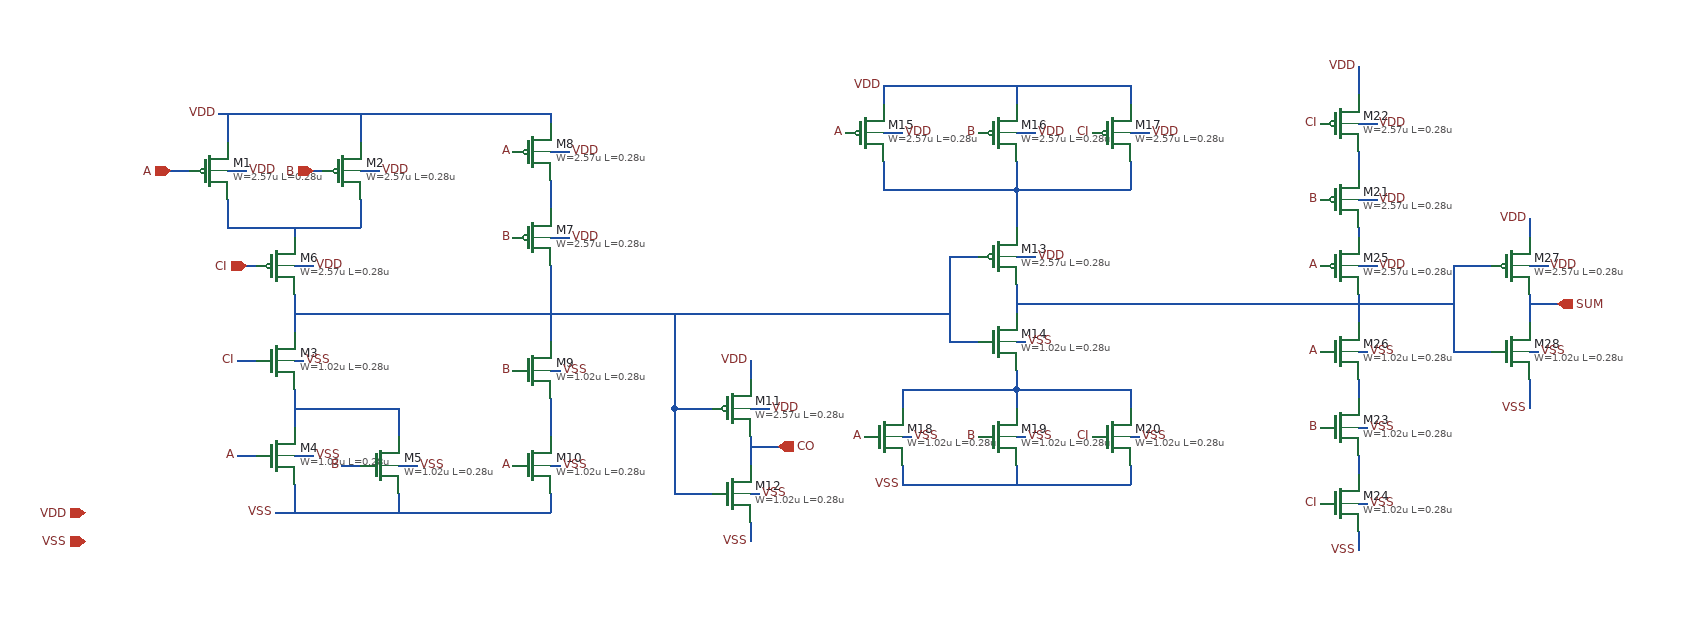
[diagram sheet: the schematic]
v {xschem version=3.4.6 file_version=1.2}
G {}
K {}
V {}
S {}
E {}
N 120 -480 120 -450 { lab=VDD}
N 260 -480 260 -450 { lab=VDD}
N 120 -390 120 -360 { lab=#net1}
N 120 -360 260 -360 { lab=#net1}
N 260 -390 260 -360 { lab=#net1}
N 190 -190 190 -150 { lab=#net2}
N 190 -90 190 -60 { lab=VSS}
N 60 -420 80 -420 { lab=A}
N 210 -420 220 -420 { lab=B}
N 190 -270 250 -270 { lab=#net3}
N 120 -420 140 -420 { lab=VDD}
N 260 -420 280 -420 { lab=VDD}
N 190 -220 200 -220 { lab=VSS}
N 190 -120 210 -120 { lab=VSS}
N 130 -220 150 -220 { lab=CI}
N 130 -120 150 -120 { lab=A}
N 140 -320 150 -320 { lab=CI}
N 190 -320 210 -320 { lab=VDD}
N 190 -360 190 -350 { lab=#net1}
N 190 -290 190 -250 { lab=#net3}
N 240 -110 260 -110 { lab=B}
N 300 -110 320 -110 { lab=VSS}
N 300 -80 300 -70 { lab=VSS}
N 190 -170 300 -170 { lab=#net2}
N 300 -170 300 -140 { lab=#net2}
N 300 -70 300 -60 { lab=VSS}
N 460 -410 460 -380 { lab=#net4}
N 460 -180 460 -140 { lab=#net5}
N 460 -320 460 -240 { lab=#net3}
N 460 -80 460 -60 { lab=VSS}
N 250 -270 460 -270 { lab=#net3}
N 670 -140 670 -110 { lab=CO}
N 590 -170 630 -170 { lab=#net3}
N 590 -170 590 -80 { lab=#net3}
N 590 -80 630 -80 { lab=#net3}
N 670 -220 670 -200 { lab=VDD}
N 460 -270 800 -270 { lab=#net3}
N 590 -270 590 -170 { lab=#net3}
N 950 -300 950 -270 { lab=#net6}
N 880 -330 920 -330 { lab=#net3}
N 880 -330 880 -240 { lab=#net3}
N 880 -240 920 -240 { lab=#net3}
N 810 -430 810 -400 { lab=#net7}
N 810 -400 950 -400 { lab=#net7}
N 950 -430 950 -400 { lab=#net7}
N 950 -400 1070 -400 { lab=#net7}
N 1070 -430 1070 -400 { lab=#net7}
N 950 -400 950 -360 { lab=#net7}
N 830 -190 830 -170 { lab=#net8}
N 900 -190 950 -190 { lab=#net8}
N 950 -200 950 -190 { lab=#net8}
N 950 -190 950 -170 { lab=#net8}
N 1070 -190 1070 -170 { lab=#net8}
N 460 -440 480 -440 { lab=VDD}
N 460 -350 480 -350 { lab=VDD}
N 810 -460 830 -460 { lab=VDD}
N 950 -460 970 -460 { lab=VDD}
N 1070 -460 1090 -460 { lab=VDD}
N 950 -330 970 -330 { lab=VDD}
N 460 -210 470 -210 { lab=VSS}
N 460 -110 470 -110 { lab=VSS}
N 670 -80 680 -80 { lab=VSS}
N 830 -140 840 -140 { lab=VSS}
N 950 -140 960 -140 { lab=VSS}
N 1070 -140 1080 -140 { lab=VSS}
N 950 -240 960 -240 { lab=VSS}
N 670 -170 690 -170 { lab=VDD}
N 950 -210 950 -200 { lab=#net8}
N 830 -190 900 -190 { lab=#net8}
N 950 -190 1070 -190 { lab=#net8}
N 1310 -40 1310 -20 { lab=VSS}
N 1310 -470 1330 -470 { lab=VDD}
N 1310 -390 1330 -390 { lab=VDD}
N 1310 -150 1320 -150 { lab=VSS}
N 1310 -70 1320 -70 { lab=VSS}
N 1310 -320 1330 -320 { lab=VDD}
N 1310 -360 1310 -350 { lab=#net9}
N 1310 -230 1320 -230 { lab=VSS}
N 1310 -200 1310 -180 { lab=#net10}
N 1310 -120 1310 -100 { lab=#net11}
N 1310 -440 1310 -420 { lab=#net12}
N 1310 -290 1310 -260 { lab=#net6}
N 800 -270 880 -270 { lab=#net3}
N 950 -280 1310 -280 { lab=#net6}
N 1490 -190 1490 -170 { lab=#net13}
N 1490 -200 1490 -190 { lab=#net13}
N 1490 -290 1490 -260 { lab=SUM}
N 1410 -320 1450 -320 { lab=#net6}
N 1410 -320 1410 -230 { lab=#net6}
N 1410 -230 1450 -230 { lab=#net6}
N 1490 -370 1490 -350 { lab=VDD}
N 1490 -230 1500 -230 { lab=VSS}
N 1490 -320 1510 -320 { lab=VDD}
N 1310 -280 1410 -280 { lab=#net6}
N 1490 -280 1520 -280 { lab=SUM}
N 670 -130 700 -130 {lab=CO}
N 460 -480 460 -470 {lab=VDD}
N 110 -480 460 -480 {lab=VDD}
N 170 -60 460 -60 {lab=VSS}
N 830 -110 830 -90 {lab=VSS}
N 830 -90 1070 -90 {lab=VSS}
N 1070 -110 1070 -90 {lab=VSS}
N 950 -110 950 -90 {lab=VSS}
N 1070 -510 1070 -490 {lab=VDD}
N 810 -510 1070 -510 {lab=VDD}
N 810 -510 810 -490 {lab=VDD}
N 950 -510 950 -490 {lab=VDD}
N 1310 -530 1310 -500 {lab=VDD}
N 670 -50 670 -30 {lab=VSS}
C {symbols/pfet_03v3.sym} 100 -420 0 0 {name=M1 L=0.28u W=2.57u m=1 nf=2 ad="'int((nf+1)/2) * W/nf * 0.18u'" pd="'2*int((nf+1)/2) * (W/nf + 0.18u)'" as="'int((nf+2)/2) * W/nf * 0.18u'" ps="'2*int((nf+2)/2) * (W/nf + 0.18u)'" nrd="'0.18u / W'" nrs="'0.18u / W'" sa=0 sb=0 sd=0 model=pfet_03v3 spiceprefix=X}
C {symbols/pfet_03v3.sym} 240 -420 0 0 {name=M2 L=0.28u W=2.57u m=1 nf=2 ad="'int((nf+1)/2) * W/nf * 0.18u'" pd="'2*int((nf+1)/2) * (W/nf + 0.18u)'" as="'int((nf+2)/2) * W/nf * 0.18u'" ps="'2*int((nf+2)/2) * (W/nf + 0.18u)'" nrd="'0.18u / W'" nrs="'0.18u / W'" sa=0 sb=0 sd=0 model=pfet_03v3 spiceprefix=X}
C {symbols/nfet_03v3.sym} 170 -220 0 0 {name=M3 L=0.28u W=1.02u m=1 nf=1 ad="'int((nf+1)/2) * W/nf * 0.18u'" pd="'2*int((nf+1)/2) * (W/nf + 0.18u)'" as="'int((nf+2)/2) * W/nf * 0.18u'" ps="'2*int((nf+2)/2) * (W/nf + 0.18u)'" nrd="'0.18u / W'" nrs="'0.18u / W'" sa=0 sb=0 sd=0 model=nfet_03v3 spiceprefix=X}
C {symbols/nfet_03v3.sym} 170 -120 0 0 {name=M4 L=0.28u W=1.02u m=1 nf=1 ad="'int((nf+1)/2) * W/nf * 0.18u'" pd="'2*int((nf+1)/2) * (W/nf + 0.18u)'" as="'int((nf+2)/2) * W/nf * 0.18u'" ps="'2*int((nf+2)/2) * (W/nf + 0.18u)'" nrd="'0.18u / W'" nrs="'0.18u / W'" sa=0 sb=0 sd=0 model=nfet_03v3 spiceprefix=X}
C {lab_wire.sym} 140 -420 2 0 {name=l4 sig_type=std_logic lab=VDD}
C {lab_wire.sym} 280 -420 2 0 {name=l5 sig_type=std_logic lab=VDD}
C {lab_wire.sym} 200 -220 2 0 {name=l6 sig_type=std_logic lab=VSS}
C {lab_wire.sym} 210 -120 2 0 {name=l7 sig_type=std_logic lab=VSS}
C {lab_wire.sym} 130 -220 0 0 {name=l8 sig_type=std_logic lab=CI
}
C {lab_wire.sym} 130 -120 0 0 {name=l9 sig_type=std_logic lab=A}
C {symbols/nfet_03v3.sym} 280 -110 0 0 {name=M5 L=0.28u W=1.02u m=1 nf=1 ad="'int((nf+1)/2) * W/nf * 0.18u'" pd="'2*int((nf+1)/2) * (W/nf + 0.18u)'" as="'int((nf+2)/2) * W/nf * 0.18u'" ps="'2*int((nf+2)/2) * (W/nf + 0.18u)'" nrd="'0.18u / W'" nrs="'0.18u / W'" sa=0 sb=0 sd=0 model=nfet_03v3 spiceprefix=X}
C {symbols/pfet_03v3.sym} 170 -320 0 0 {name=M6 L=0.28u W=2.57u m=1 nf=2 ad="'int((nf+1)/2) * W/nf * 0.18u'" pd="'2*int((nf+1)/2) * (W/nf + 0.18u)'" as="'int((nf+2)/2) * W/nf * 0.18u'" ps="'2*int((nf+2)/2) * (W/nf + 0.18u)'" nrd="'0.18u / W'" nrs="'0.18u / W'" sa=0 sb=0 sd=0 model=pfet_03v3 spiceprefix=X}
C {lab_wire.sym} 210 -320 2 0 {name=l10 sig_type=std_logic lab=VDD}
C {lab_wire.sym} 240 -110 0 0 {name=l11 sig_type=std_logic lab=B
}
C {lab_wire.sym} 320 -110 2 0 {name=l12 sig_type=std_logic lab=VSS}
C {symbols/pfet_03v3.sym} 440 -350 0 0 {name=M7 L=0.28u W=2.57u m=1 nf=2 ad="'int((nf+1)/2) * W/nf * 0.18u'" pd="'2*int((nf+1)/2) * (W/nf + 0.18u)'" as="'int((nf+2)/2) * W/nf * 0.18u'" ps="'2*int((nf+2)/2) * (W/nf + 0.18u)'" nrd="'0.18u / W'" nrs="'0.18u / W'" sa=0 sb=0 sd=0 model=pfet_03v3 spiceprefix=X}
C {symbols/pfet_03v3.sym} 440 -440 0 0 {name=M8 L=0.28u W=2.57u m=1 nf=2 ad="'int((nf+1)/2) * W/nf * 0.18u'" pd="'2*int((nf+1)/2) * (W/nf + 0.18u)'" as="'int((nf+2)/2) * W/nf * 0.18u'" ps="'2*int((nf+2)/2) * (W/nf + 0.18u)'" nrd="'0.18u / W'" nrs="'0.18u / W'" sa=0 sb=0 sd=0 model=pfet_03v3 spiceprefix=X}
C {symbols/nfet_03v3.sym} 440 -210 0 0 {name=M9 L=0.28u W=1.02u m=1 nf=1 ad="'int((nf+1)/2) * W/nf * 0.18u'" pd="'2*int((nf+1)/2) * (W/nf + 0.18u)'" as="'int((nf+2)/2) * W/nf * 0.18u'" ps="'2*int((nf+2)/2) * (W/nf + 0.18u)'" nrd="'0.18u / W'" nrs="'0.18u / W'" sa=0 sb=0 sd=0 model=nfet_03v3 spiceprefix=X}
C {symbols/nfet_03v3.sym} 440 -110 0 0 {name=M10 L=0.28u W=1.02u m=1 nf=1 ad="'int((nf+1)/2) * W/nf * 0.18u'" pd="'2*int((nf+1)/2) * (W/nf + 0.18u)'" as="'int((nf+2)/2) * W/nf * 0.18u'" ps="'2*int((nf+2)/2) * (W/nf + 0.18u)'" nrd="'0.18u / W'" nrs="'0.18u / W'" sa=0 sb=0 sd=0 model=nfet_03v3 spiceprefix=X}
C {symbols/pfet_03v3.sym} 650 -170 0 0 {name=M11 L=0.28u W=2.57u m=1 nf=2 ad="'int((nf+1)/2) * W/nf * 0.18u'" pd="'2*int((nf+1)/2) * (W/nf + 0.18u)'" as="'int((nf+2)/2) * W/nf * 0.18u'" ps="'2*int((nf+2)/2) * (W/nf + 0.18u)'" nrd="'0.18u / W'" nrs="'0.18u / W'" sa=0 sb=0 sd=0 model=pfet_03v3 spiceprefix=X}
C {symbols/nfet_03v3.sym} 650 -80 0 0 {name=M12 L=0.28u W=1.02u m=1 nf=1 ad="'int((nf+1)/2) * W/nf * 0.18u'" pd="'2*int((nf+1)/2) * (W/nf + 0.18u)'" as="'int((nf+2)/2) * W/nf * 0.18u'" ps="'2*int((nf+2)/2) * (W/nf + 0.18u)'" nrd="'0.18u / W'" nrs="'0.18u / W'" sa=0 sb=0 sd=0 model=nfet_03v3 spiceprefix=X}
C {symbols/pfet_03v3.sym} 930 -330 0 0 {name=M13 L=0.28u W=2.57u m=1 nf=2 ad="'int((nf+1)/2) * W/nf * 0.18u'" pd="'2*int((nf+1)/2) * (W/nf + 0.18u)'" as="'int((nf+2)/2) * W/nf * 0.18u'" ps="'2*int((nf+2)/2) * (W/nf + 0.18u)'" nrd="'0.18u / W'" nrs="'0.18u / W'" sa=0 sb=0 sd=0 model=pfet_03v3 spiceprefix=X}
C {symbols/nfet_03v3.sym} 930 -240 0 0 {name=M14 L=0.28u W=1.02u m=1 nf=1 ad="'int((nf+1)/2) * W/nf * 0.18u'" pd="'2*int((nf+1)/2) * (W/nf + 0.18u)'" as="'int((nf+2)/2) * W/nf * 0.18u'" ps="'2*int((nf+2)/2) * (W/nf + 0.18u)'" nrd="'0.18u / W'" nrs="'0.18u / W'" sa=0 sb=0 sd=0 model=nfet_03v3 spiceprefix=X}
C {symbols/pfet_03v3.sym} 790 -460 0 0 {name=M15 L=0.28u W=2.57u m=1 nf=2 ad="'int((nf+1)/2) * W/nf * 0.18u'" pd="'2*int((nf+1)/2) * (W/nf + 0.18u)'" as="'int((nf+2)/2) * W/nf * 0.18u'" ps="'2*int((nf+2)/2) * (W/nf + 0.18u)'" nrd="'0.18u / W'" nrs="'0.18u / W'" sa=0 sb=0 sd=0 model=pfet_03v3 spiceprefix=X}
C {symbols/pfet_03v3.sym} 930 -460 0 0 {name=M16 L=0.28u W=2.57u m=1 nf=2 ad="'int((nf+1)/2) * W/nf * 0.18u'" pd="'2*int((nf+1)/2) * (W/nf + 0.18u)'" as="'int((nf+2)/2) * W/nf * 0.18u'" ps="'2*int((nf+2)/2) * (W/nf + 0.18u)'" nrd="'0.18u / W'" nrs="'0.18u / W'" sa=0 sb=0 sd=0 model=pfet_03v3 spiceprefix=X}
C {symbols/pfet_03v3.sym} 1050 -460 0 0 {name=M17 L=0.28u W=2.57u m=1 nf=2 ad="'int((nf+1)/2) * W/nf * 0.18u'" pd="'2*int((nf+1)/2) * (W/nf + 0.18u)'" as="'int((nf+2)/2) * W/nf * 0.18u'" ps="'2*int((nf+2)/2) * (W/nf + 0.18u)'" nrd="'0.18u / W'" nrs="'0.18u / W'" sa=0 sb=0 sd=0 model=pfet_03v3 spiceprefix=X}
C {symbols/nfet_03v3.sym} 810 -140 0 0 {name=M18 L=0.28u W=1.02u m=1 nf=1 ad="'int((nf+1)/2) * W/nf * 0.18u'" pd="'2*int((nf+1)/2) * (W/nf + 0.18u)'" as="'int((nf+2)/2) * W/nf * 0.18u'" ps="'2*int((nf+2)/2) * (W/nf + 0.18u)'" nrd="'0.18u / W'" nrs="'0.18u / W'" sa=0 sb=0 sd=0 model=nfet_03v3 spiceprefix=X}
C {symbols/nfet_03v3.sym} 930 -140 0 0 {name=M19 L=0.28u W=1.02u m=1 nf=1 ad="'int((nf+1)/2) * W/nf * 0.18u'" pd="'2*int((nf+1)/2) * (W/nf + 0.18u)'" as="'int((nf+2)/2) * W/nf * 0.18u'" ps="'2*int((nf+2)/2) * (W/nf + 0.18u)'" nrd="'0.18u / W'" nrs="'0.18u / W'" sa=0 sb=0 sd=0 model=nfet_03v3 spiceprefix=X}
C {symbols/nfet_03v3.sym} 1050 -140 0 0 {name=M20 L=0.28u W=1.02u m=1 nf=1 ad="'int((nf+1)/2) * W/nf * 0.18u'" pd="'2*int((nf+1)/2) * (W/nf + 0.18u)'" as="'int((nf+2)/2) * W/nf * 0.18u'" ps="'2*int((nf+2)/2) * (W/nf + 0.18u)'" nrd="'0.18u / W'" nrs="'0.18u / W'" sa=0 sb=0 sd=0 model=nfet_03v3 spiceprefix=X}
C {lab_wire.sym} 480 -440 2 0 {name=l24 sig_type=std_logic lab=VDD}
C {lab_wire.sym} 480 -350 2 0 {name=l25 sig_type=std_logic lab=VDD}
C {lab_wire.sym} 830 -460 2 0 {name=l26 sig_type=std_logic lab=VDD}
C {lab_wire.sym} 970 -460 2 0 {name=l27 sig_type=std_logic lab=VDD}
C {lab_wire.sym} 1090 -460 2 0 {name=l28 sig_type=std_logic lab=VDD}
C {lab_wire.sym} 970 -330 2 0 {name=l29 sig_type=std_logic lab=VDD}
C {lab_wire.sym} 470 -210 2 0 {name=l30 sig_type=std_logic lab=VSS}
C {lab_wire.sym} 470 -110 2 0 {name=l31 sig_type=std_logic lab=VSS}
C {lab_wire.sym} 680 -80 2 0 {name=l32 sig_type=std_logic lab=VSS}
C {lab_wire.sym} 840 -140 2 0 {name=l34 sig_type=std_logic lab=VSS}
C {lab_wire.sym} 960 -140 2 0 {name=l35 sig_type=std_logic lab=VSS}
C {lab_wire.sym} 1080 -140 2 0 {name=l36 sig_type=std_logic lab=VSS}
C {lab_wire.sym} 960 -240 2 0 {name=l37 sig_type=std_logic lab=VSS}
C {lab_wire.sym} 690 -170 2 0 {name=l33 sig_type=std_logic lab=VDD}
C {symbols/pfet_03v3.sym} 1290 -390 0 0 {name=M21 L=0.28u W=2.57u m=1 nf=2 ad="'int((nf+1)/2) * W/nf * 0.18u'" pd="'2*int((nf+1)/2) * (W/nf + 0.18u)'" as="'int((nf+2)/2) * W/nf * 0.18u'" ps="'2*int((nf+2)/2) * (W/nf + 0.18u)'" nrd="'0.18u / W'" nrs="'0.18u / W'" sa=0 sb=0 sd=0 model=pfet_03v3 spiceprefix=X}
C {symbols/pfet_03v3.sym} 1290 -470 0 0 {name=M22 L=0.28u W=2.57u m=1 nf=2 ad="'int((nf+1)/2) * W/nf * 0.18u'" pd="'2*int((nf+1)/2) * (W/nf + 0.18u)'" as="'int((nf+2)/2) * W/nf * 0.18u'" ps="'2*int((nf+2)/2) * (W/nf + 0.18u)'" nrd="'0.18u / W'" nrs="'0.18u / W'" sa=0 sb=0 sd=0 model=pfet_03v3 spiceprefix=X}
C {symbols/nfet_03v3.sym} 1290 -150 0 0 {name=M23 L=0.28u W=1.02u m=1 nf=1 ad="'int((nf+1)/2) * W/nf * 0.18u'" pd="'2*int((nf+1)/2) * (W/nf + 0.18u)'" as="'int((nf+2)/2) * W/nf * 0.18u'" ps="'2*int((nf+2)/2) * (W/nf + 0.18u)'" nrd="'0.18u / W'" nrs="'0.18u / W'" sa=0 sb=0 sd=0 model=nfet_03v3 spiceprefix=X}
C {symbols/nfet_03v3.sym} 1290 -70 0 0 {name=M24 L=0.28u W=1.02u m=1 nf=1 ad="'int((nf+1)/2) * W/nf * 0.18u'" pd="'2*int((nf+1)/2) * (W/nf + 0.18u)'" as="'int((nf+2)/2) * W/nf * 0.18u'" ps="'2*int((nf+2)/2) * (W/nf + 0.18u)'" nrd="'0.18u / W'" nrs="'0.18u / W'" sa=0 sb=0 sd=0 model=nfet_03v3 spiceprefix=X}
C {lab_wire.sym} 1330 -470 2 0 {name=l40 sig_type=std_logic lab=VDD}
C {lab_wire.sym} 1330 -390 2 0 {name=l41 sig_type=std_logic lab=VDD}
C {lab_wire.sym} 1320 -150 2 0 {name=l42 sig_type=std_logic lab=VSS}
C {lab_wire.sym} 1320 -70 2 0 {name=l43 sig_type=std_logic lab=VSS}
C {symbols/pfet_03v3.sym} 1290 -320 0 0 {name=M25 L=0.28u W=2.57u m=1 nf=2 ad="'int((nf+1)/2) * W/nf * 0.18u'" pd="'2*int((nf+1)/2) * (W/nf + 0.18u)'" as="'int((nf+2)/2) * W/nf * 0.18u'" ps="'2*int((nf+2)/2) * (W/nf + 0.18u)'" nrd="'0.18u / W'" nrs="'0.18u / W'" sa=0 sb=0 sd=0 model=pfet_03v3 spiceprefix=X}
C {lab_wire.sym} 1330 -320 2 0 {name=l44 sig_type=std_logic lab=VDD}
C {symbols/nfet_03v3.sym} 1290 -230 0 0 {name=M26 L=0.28u W=1.02u m=1 nf=1 ad="'int((nf+1)/2) * W/nf * 0.18u'" pd="'2*int((nf+1)/2) * (W/nf + 0.18u)'" as="'int((nf+2)/2) * W/nf * 0.18u'" ps="'2*int((nf+2)/2) * (W/nf + 0.18u)'" nrd="'0.18u / W'" nrs="'0.18u / W'" sa=0 sb=0 sd=0 model=nfet_03v3 spiceprefix=X}
C {lab_wire.sym} 1320 -230 2 0 {name=l45 sig_type=std_logic lab=VSS}
C {lab_wire.sym} 420 -210 0 0 {name=l46 sig_type=std_logic lab=B}
C {lab_wire.sym} 420 -110 0 0 {name=l47 sig_type=std_logic lab=A
}
C {lab_wire.sym} 420 -440 0 0 {name=l48 sig_type=std_logic lab=A}
C {lab_wire.sym} 420 -350 0 0 {name=l49 sig_type=std_logic lab=B
}
C {lab_wire.sym} 770 -460 0 0 {name=l50 sig_type=std_logic lab=A}
C {lab_wire.sym} 910 -460 0 0 {name=l51 sig_type=std_logic lab=B
}
C {lab_wire.sym} 1030 -460 0 0 {name=l52 sig_type=std_logic lab=CI
}
C {lab_wire.sym} 790 -140 0 0 {name=l53 sig_type=std_logic lab=A}
C {lab_wire.sym} 910 -140 0 0 {name=l54 sig_type=std_logic lab=B
}
C {lab_wire.sym} 1030 -140 0 0 {name=l55 sig_type=std_logic lab=CI
}
C {lab_wire.sym} 1270 -470 0 0 {name=l56 sig_type=std_logic lab=CI}
C {lab_wire.sym} 1270 -390 0 0 {name=l57 sig_type=std_logic lab=B
}
C {lab_wire.sym} 1270 -320 0 0 {name=l58 sig_type=std_logic lab=A
}
C {lab_wire.sym} 1270 -230 0 0 {name=l59 sig_type=std_logic lab=A}
C {lab_wire.sym} 1270 -150 0 0 {name=l60 sig_type=std_logic lab=B
}
C {lab_wire.sym} 1270 -70 0 0 {name=l61 sig_type=std_logic lab=CI
}
C {symbols/pfet_03v3.sym} 1470 -320 0 0 {name=M27 L=0.28u W=2.57u m=1 nf=2 ad="'int((nf+1)/2) * W/nf * 0.18u'" pd="'2*int((nf+1)/2) * (W/nf + 0.18u)'" as="'int((nf+2)/2) * W/nf * 0.18u'" ps="'2*int((nf+2)/2) * (W/nf + 0.18u)'" nrd="'0.18u / W'" nrs="'0.18u / W'" sa=0 sb=0 sd=0 model=pfet_03v3 spiceprefix=X}
C {symbols/nfet_03v3.sym} 1470 -230 0 0 {name=M28 L=0.28u W=1.02u m=1 nf=1 ad="'int((nf+1)/2) * W/nf * 0.18u'" pd="'2*int((nf+1)/2) * (W/nf + 0.18u)'" as="'int((nf+2)/2) * W/nf * 0.18u'" ps="'2*int((nf+2)/2) * (W/nf + 0.18u)'" nrd="'0.18u / W'" nrs="'0.18u / W'" sa=0 sb=0 sd=0 model=nfet_03v3 spiceprefix=X}
C {lab_wire.sym} 1500 -230 2 0 {name=l64 sig_type=std_logic lab=VSS}
C {lab_wire.sym} 1510 -320 2 0 {name=l65 sig_type=std_logic lab=VDD}
C {ipin.sym} 60 -420 0 0 {name=p1 lab=A}
C {ipin.sym} 210 -420 0 0 {name=p2 lab=B}
C {ipin.sym} 140 -320 0 0 {name=p3 lab=CI}
C {opin.sym} 1520 -280 0 0 {name=p4 lab=SUM}
C {opin.sym} 700 -130 0 0 {name=p5 lab=CO}
C {ipin.sym} -30 -60 0 0 {name=p6 lab=VDD}
C {ipin.sym} -30 -30 0 0 {name=p7 lab=VSS}
C {lab_pin.sym} 170 -60 0 0 {name=p8 sig_type=std_logic lab=VSS}
C {lab_pin.sym} 110 -480 0 0 {name=p9 sig_type=std_logic lab=VDD}
C {lab_pin.sym} 810 -510 0 0 {name=p10 sig_type=std_logic lab=VDD}
C {lab_pin.sym} 1310 -530 0 0 {name=p11 sig_type=std_logic lab=VDD}
C {lab_pin.sym} 1490 -370 0 0 {name=p12 sig_type=std_logic lab=VDD}
C {lab_pin.sym} 670 -30 0 0 {name=p13 sig_type=std_logic lab=VSS}
C {lab_pin.sym} 830 -90 0 0 {name=p14 sig_type=std_logic lab=VSS}
C {lab_pin.sym} 1310 -20 0 0 {name=p15 sig_type=std_logic lab=VSS}
C {lab_pin.sym} 670 -220 0 0 {name=p16 sig_type=std_logic lab=VDD}
C {lab_pin.sym} 1490 -170 0 0 {name=p17 sig_type=std_logic lab=VSS}
